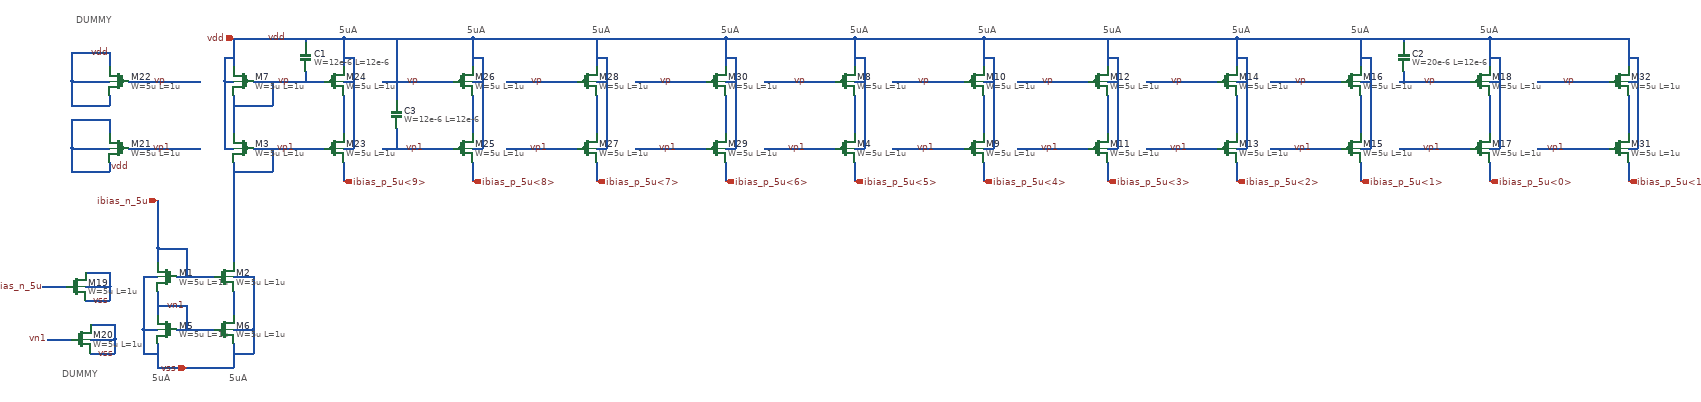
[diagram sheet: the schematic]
v {xschem version=3.4.8RC file_version=1.3}
G {}
K {}
V {}
S {}
F {}
E {}
T {5uA} -600 -260 0 0 0.2 0.2 {}
T {5uA} -440 -260 0 0 0.2 0.2 {}
T {5uA} 860 -990 0 0 0.2 0.2 {}
T {5uA} 1130 -990 0 0 0.2 0.2 {}
T {5uA} 1390 -990 0 0 0.2 0.2 {}
T {5uA} 1660 -990 0 0 0.2 0.2 {}
T {5uA} 1910 -990 0 0 0.2 0.2 {}
T {5uA} 2180 -990 0 0 0.2 0.2 {}
T {DUMMY} -760 -1010 0 0 0.4 0.4 {}
T {DUMMY} -790 -270 0 0 0.4 0.4 {}
T {5uA} -210 -990 0 0 0.2 0.2 {}
T {5uA} 60 -990 0 0 0.2 0.2 {}
T {5uA} 320 -990 0 0 0.2 0.2 {}
T {5uA} 590 -990 0 0 0.2 0.2 {}
N -550 -460 -470 -460 {lab=ibias_n_5u}
N -530 -520 -530 -460 {lab=ibias_n_5u}
N -590 -520 -530 -520 {lab=ibias_n_5u}
N -590 -520 -590 -490 {lab=ibias_n_5u}
N -590 -430 -590 -380 {lab=vn1}
N -590 -270 -430 -270 {lab=vss}
N -430 -430 -430 -380 {lab=#net1}
N -620 -460 -590 -460 {lab=vss}
N -620 -460 -620 -410 {lab=vss}
N -430 -460 -390 -460 {lab=vss}
N -390 -460 -390 -420 {lab=vss}
N -390 -420 -390 -410 {lab=vss}
N -390 -730 -240 -730 {lab=vp1}
N -430 -680 -350 -680 {lab=vp1}
N -350 -730 -350 -710 {lab=vp1}
N 870 -820 870 -760 {lab=#net2}
N -430 -960 -200 -960 {lab=vdd}
N -450 -730 -430 -730 {lab=vdd}
N 870 -730 890 -730 {lab=vdd}
N 870 -700 870 -660 {lab=ibias_p_5u<5>}
N -430 -700 -430 -590 {lab=vp1}
N -430 -530 -430 -490 {lab=vp1}
N -590 -540 -590 -520 {lab=ibias_n_5u}
N -550 -350 -470 -350 {lab=vn1}
N -590 -320 -590 -270 {lab=vss}
N -430 -320 -430 -270 {lab=vss}
N -620 -350 -590 -350 {lab=vss}
N -620 -350 -620 -300 {lab=vss}
N -620 -300 -590 -300 {lab=vss}
N -430 -350 -390 -350 {lab=vss}
N -390 -350 -390 -310 {lab=vss}
N -390 -310 -390 -300 {lab=vss}
N -430 -300 -390 -300 {lab=vss}
N -530 -400 -530 -350 {lab=vn1}
N -590 -400 -530 -400 {lab=vn1}
N -390 -410 -390 -350 {lab=vss}
N -620 -420 -620 -350 {lab=vss}
N -350 -710 -350 -680 {lab=vp1}
N -390 -870 -240 -870 {lab=vp}
N -430 -820 -350 -820 {lab=vp}
N -350 -870 -350 -850 {lab=vp}
N 870 -960 870 -900 {lab=vdd}
N -430 -960 -430 -900 {lab=vdd}
N -450 -870 -430 -870 {lab=vdd}
N -450 -920 -450 -870 {lab=vdd}
N -450 -920 -430 -920 {lab=vdd}
N 870 -870 890 -870 {lab=vdd}
N 890 -920 890 -870 {lab=vdd}
N 870 -920 890 -920 {lab=vdd}
N 870 -840 870 -800 {lab=#net2}
N -350 -850 -350 -820 {lab=vp}
N -430 -840 -430 -810 {lab=vp}
N -450 -870 -450 -730 {lab=vdd}
N 890 -880 890 -730 {lab=vdd}
N 950 -730 1100 -730 {lab=vp1}
N 1140 -820 1140 -760 {lab=#net3}
N 1140 -730 1160 -730 {lab=vdd}
N 1140 -700 1140 -660 {lab=ibias_p_5u<4>}
N 950 -870 1100 -870 {lab=vp}
N 1140 -960 1140 -900 {lab=vdd}
N 1140 -870 1160 -870 {lab=vdd}
N 1160 -920 1160 -870 {lab=vdd}
N 1140 -920 1160 -920 {lab=vdd}
N 1140 -840 1140 -800 {lab=#net3}
N 1160 -880 1160 -730 {lab=vdd}
N 870 -960 1140 -960 {lab=vdd}
N 1210 -730 1360 -730 {lab=vp1}
N 1400 -820 1400 -760 {lab=#net4}
N 1400 -730 1420 -730 {lab=vdd}
N 1400 -700 1400 -660 {lab=ibias_p_5u<3>}
N 1210 -870 1360 -870 {lab=vp}
N 1400 -870 1420 -870 {lab=vdd}
N 1420 -920 1420 -870 {lab=vdd}
N 1400 -920 1420 -920 {lab=vdd}
N 1400 -840 1400 -800 {lab=#net4}
N 1420 -880 1420 -730 {lab=vdd}
N 1480 -730 1630 -730 {lab=vp1}
N 1670 -820 1670 -760 {lab=#net5}
N 1670 -730 1690 -730 {lab=vdd}
N 1670 -700 1670 -660 {lab=ibias_p_5u<2>}
N 1480 -870 1630 -870 {lab=vp}
N 1670 -870 1690 -870 {lab=vdd}
N 1690 -920 1690 -870 {lab=vdd}
N 1670 -920 1690 -920 {lab=vdd}
N 1670 -840 1670 -800 {lab=#net5}
N 1690 -880 1690 -730 {lab=vdd}
N 1140 -960 1670 -960 {lab=vdd}
N 1670 -960 1670 -900 {lab=vdd}
N 1400 -960 1400 -900 {lab=vdd}
N 1740 -730 1890 -730 {lab=vp1}
N 1930 -820 1930 -760 {lab=#net6}
N 1930 -730 1950 -730 {lab=vdd}
N 1930 -700 1930 -660 {lab=ibias_p_5u<1>}
N 1740 -870 1890 -870 {lab=vp}
N 1930 -870 1950 -870 {lab=vdd}
N 1950 -920 1950 -870 {lab=vdd}
N 1930 -920 1950 -920 {lab=vdd}
N 1930 -840 1930 -800 {lab=#net6}
N 1950 -880 1950 -730 {lab=vdd}
N 2010 -730 2160 -730 {lab=vp1}
N 2200 -820 2200 -760 {lab=#net7}
N 2200 -730 2220 -730 {lab=vdd}
N 2200 -700 2200 -660 {lab=ibias_p_5u<0>}
N 2010 -870 2160 -870 {lab=vp}
N 2200 -870 2220 -870 {lab=vdd}
N 2220 -920 2220 -870 {lab=vdd}
N 2200 -920 2220 -920 {lab=vdd}
N 2200 -840 2200 -800 {lab=#net7}
N 2220 -880 2220 -730 {lab=vdd}
N 1670 -960 2200 -960 {lab=vdd}
N 2200 -960 2200 -900 {lab=vdd}
N 1930 -960 1930 -900 {lab=vdd}
N -590 -620 -590 -540 {lab=ibias_n_5u}
N -430 -590 -430 -530 {lab=vp1}
N -830 -440 -780 -440 {lab=ibias_n_5u}
N -740 -470 -690 -470 {lab=vss}
N -690 -470 -690 -440 {lab=vss}
N -740 -440 -690 -440 {lab=vss}
N -690 -440 -690 -410 {lab=vss}
N -740 -410 -690 -410 {lab=vss}
N -820 -330 -770 -330 {lab=vn1}
N -730 -360 -680 -360 {lab=vss}
N -680 -360 -680 -330 {lab=vss}
N -730 -330 -680 -330 {lab=vss}
N -680 -330 -680 -300 {lab=vss}
N -730 -300 -680 -300 {lab=vss}
N -650 -730 -500 -730 {lab=vp1}
N -650 -870 -500 -870 {lab=vp}
N -710 -870 -690 -870 {lab=vdd}
N -690 -930 -690 -900 {lab=vdd}
N -770 -930 -690 -930 {lab=vdd}
N -770 -930 -770 -870 {lab=vdd}
N -770 -870 -710 -870 {lab=vdd}
N -770 -870 -770 -820 {lab=vdd}
N -770 -820 -690 -820 {lab=vdd}
N -690 -840 -690 -820 {lab=vdd}
N -710 -730 -690 -730 {lab=vdd}
N -690 -790 -690 -760 {lab=vdd}
N -770 -790 -690 -790 {lab=vdd}
N -770 -790 -770 -730 {lab=vdd}
N -770 -730 -710 -730 {lab=vdd}
N -770 -730 -770 -680 {lab=vdd}
N -770 -680 -690 -680 {lab=vdd}
N -690 -700 -690 -680 {lab=vdd}
N -280 -960 -280 -950 {lab=vdd}
N -280 -890 -280 -870 {lab=vp}
N -200 -820 -200 -760 {lab=#net8}
N -200 -730 -180 -730 {lab=vdd}
N -200 -700 -200 -660 {lab=ibias_p_5u<9>}
N -200 -960 -200 -900 {lab=vdd}
N -200 -870 -180 -870 {lab=vdd}
N -180 -920 -180 -870 {lab=vdd}
N -200 -920 -180 -920 {lab=vdd}
N -200 -840 -200 -800 {lab=#net8}
N -180 -880 -180 -730 {lab=vdd}
N -120 -730 30 -730 {lab=vp1}
N 70 -820 70 -760 {lab=#net9}
N 70 -730 90 -730 {lab=vdd}
N 70 -700 70 -660 {lab=ibias_p_5u<8>}
N -120 -870 30 -870 {lab=vp}
N 70 -960 70 -900 {lab=vdd}
N 70 -870 90 -870 {lab=vdd}
N 90 -920 90 -870 {lab=vdd}
N 70 -920 90 -920 {lab=vdd}
N 70 -840 70 -800 {lab=#net9}
N 90 -880 90 -730 {lab=vdd}
N -200 -960 70 -960 {lab=vdd}
N 140 -730 290 -730 {lab=vp1}
N 330 -820 330 -760 {lab=#net10}
N 330 -730 350 -730 {lab=vdd}
N 330 -700 330 -660 {lab=ibias_p_5u<7>}
N 140 -870 290 -870 {lab=vp}
N 330 -870 350 -870 {lab=vdd}
N 350 -920 350 -870 {lab=vdd}
N 330 -920 350 -920 {lab=vdd}
N 330 -840 330 -800 {lab=#net10}
N 350 -880 350 -730 {lab=vdd}
N 410 -730 560 -730 {lab=vp1}
N 600 -820 600 -760 {lab=#net11}
N 600 -730 620 -730 {lab=vdd}
N 600 -700 600 -660 {lab=ibias_p_5u<6>}
N 410 -870 560 -870 {lab=vp}
N 600 -870 620 -870 {lab=vdd}
N 620 -920 620 -870 {lab=vdd}
N 600 -920 620 -920 {lab=vdd}
N 600 -840 600 -800 {lab=#net11}
N 620 -880 620 -730 {lab=vdd}
N 70 -960 600 -960 {lab=vdd}
N 600 -960 600 -900 {lab=vdd}
N 330 -960 330 -900 {lab=vdd}
N -90 -960 -90 -830 {lab=vdd}
N -90 -770 -90 -730 {lab=vp1}
N 600 -960 870 -960 {lab=vdd}
N 680 -870 830 -870 {lab=vp}
N 680 -730 830 -730 {lab=vp1}
N 2020 -960 2020 -950 {lab=vdd}
N 2020 -890 2020 -870 {lab=vp}
N 2300 -730 2450 -730 {lab=vp1}
N 2490 -820 2490 -760 {lab=#net12}
N 2490 -730 2510 -730 {lab=vdd}
N 2490 -700 2490 -660 {lab=ibias_p_5u<10>}
N 2300 -870 2450 -870 {lab=vp}
N 2490 -870 2510 -870 {lab=vdd}
N 2510 -920 2510 -870 {lab=vdd}
N 2490 -920 2510 -920 {lab=vdd}
N 2490 -840 2490 -800 {lab=#net12}
N 2510 -880 2510 -730 {lab=vdd}
N 2490 -960 2490 -900 {lab=vdd}
N 2200 -960 2490 -960 {lab=vdd}
N -430 -810 -430 -760 {lab=vp}
C {symbols/nfet_05v0.sym} -570 -460 0 1 {name=M1
L=1u
W=5u
nf=1
m=1
ad="'int((nf+1)/2) * W/nf * 0.18u'"
pd="'2*int((nf+1)/2) * (W/nf + 0.18u)'"
as="'int((nf+2)/2) * W/nf * 0.18u'"
ps="'2*int((nf+2)/2) * (W/nf + 0.18u)'"
nrd="'0.18u / W'" nrs="'0.18u / W'"
sa=0 sb=0 sd=0
model=nfet_05v0
spiceprefix=X
}
C {symbols/nfet_05v0.sym} -450 -460 0 0 {name=M2
L=1u
W=5u
nf=1
m=1
ad="'int((nf+1)/2) * W/nf * 0.18u'"
pd="'2*int((nf+1)/2) * (W/nf + 0.18u)'"
as="'int((nf+2)/2) * W/nf * 0.18u'"
ps="'2*int((nf+2)/2) * (W/nf + 0.18u)'"
nrd="'0.18u / W'" nrs="'0.18u / W'"
sa=0 sb=0 sd=0
model=nfet_05v0
spiceprefix=X
}
C {symbols/pfet_05v0.sym} -410 -730 0 1 {name=M3
L=1u
W=5u
nf=1
m=1
ad="'int((nf+1)/2) * W/nf * 0.18u'"
pd="'2*int((nf+1)/2) * (W/nf + 0.18u)'"
as="'int((nf+2)/2) * W/nf * 0.18u'"
ps="'2*int((nf+2)/2) * (W/nf + 0.18u)'"
nrd="'0.18u / W'" nrs="'0.18u / W'"
sa=0 sb=0 sd=0
model=pfet_05v0
spiceprefix=X
}
C {symbols/pfet_05v0.sym} 850 -730 0 0 {name=M4
L=1u
W=5u
nf=1
m=1
ad="'int((nf+1)/2) * W/nf * 0.18u'"
pd="'2*int((nf+1)/2) * (W/nf + 0.18u)'"
as="'int((nf+2)/2) * W/nf * 0.18u'"
ps="'2*int((nf+2)/2) * (W/nf + 0.18u)'"
nrd="'0.18u / W'" nrs="'0.18u / W'"
sa=0 sb=0 sd=0
model=pfet_05v0
spiceprefix=X
}
C {devices/lab_pin.sym} -320 -960 1 0 {name=l5 sig_type=std_logic lab=vdd}
C {symbols/nfet_05v0.sym} -570 -350 0 1 {name=M5
L=1u
W=5u
nf=1
m=1
ad="'int((nf+1)/2) * W/nf * 0.18u'"
pd="'2*int((nf+1)/2) * (W/nf + 0.18u)'"
as="'int((nf+2)/2) * W/nf * 0.18u'"
ps="'2*int((nf+2)/2) * (W/nf + 0.18u)'"
nrd="'0.18u / W'" nrs="'0.18u / W'"
sa=0 sb=0 sd=0
model=nfet_05v0
spiceprefix=X
}
C {symbols/nfet_05v0.sym} -450 -350 0 0 {name=M6
L=1u
W=5u
nf=1
m=1
ad="'int((nf+1)/2) * W/nf * 0.18u'"
pd="'2*int((nf+1)/2) * (W/nf + 0.18u)'"
as="'int((nf+2)/2) * W/nf * 0.18u'"
ps="'2*int((nf+2)/2) * (W/nf + 0.18u)'"
nrd="'0.18u / W'" nrs="'0.18u / W'"
sa=0 sb=0 sd=0
model=nfet_05v0
spiceprefix=X
}
C {symbols/pfet_05v0.sym} -410 -870 0 1 {name=M7
L=1u
W=5u
nf=1
m=1
ad="'int((nf+1)/2) * W/nf * 0.18u'"
pd="'2*int((nf+1)/2) * (W/nf + 0.18u)'"
as="'int((nf+2)/2) * W/nf * 0.18u'"
ps="'2*int((nf+2)/2) * (W/nf + 0.18u)'"
nrd="'0.18u / W'" nrs="'0.18u / W'"
sa=0 sb=0 sd=0
model=pfet_05v0
spiceprefix=X
}
C {symbols/pfet_05v0.sym} 850 -870 0 0 {name=M8
L=1u
W=5u
nf=1
m=1
ad="'int((nf+1)/2) * W/nf * 0.18u'"
pd="'2*int((nf+1)/2) * (W/nf + 0.18u)'"
as="'int((nf+2)/2) * W/nf * 0.18u'"
ps="'2*int((nf+2)/2) * (W/nf + 0.18u)'"
nrd="'0.18u / W'" nrs="'0.18u / W'"
sa=0 sb=0 sd=0
model=pfet_05v0
spiceprefix=X
}
C {devices/lab_pin.sym} -310 -870 1 0 {name=l7 sig_type=std_logic lab=vp}
C {devices/lab_pin.sym} -300 -730 1 0 {name=l3 sig_type=std_logic lab=vp1}
C {devices/lab_pin.sym} -530 -400 1 0 {name=l8 sig_type=std_logic lab=vn1}
C {symbols/pfet_05v0.sym} 1120 -730 0 0 {name=M9
L=1u
W=5u
nf=1
m=1
ad="'int((nf+1)/2) * W/nf * 0.18u'"
pd="'2*int((nf+1)/2) * (W/nf + 0.18u)'"
as="'int((nf+2)/2) * W/nf * 0.18u'"
ps="'2*int((nf+2)/2) * (W/nf + 0.18u)'"
nrd="'0.18u / W'" nrs="'0.18u / W'"
sa=0 sb=0 sd=0
model=pfet_05v0
spiceprefix=X
}
C {symbols/pfet_05v0.sym} 1120 -870 0 0 {name=M10
L=1u
W=5u
nf=1
m=1
ad="'int((nf+1)/2) * W/nf * 0.18u'"
pd="'2*int((nf+1)/2) * (W/nf + 0.18u)'"
as="'int((nf+2)/2) * W/nf * 0.18u'"
ps="'2*int((nf+2)/2) * (W/nf + 0.18u)'"
nrd="'0.18u / W'" nrs="'0.18u / W'"
sa=0 sb=0 sd=0
model=pfet_05v0
spiceprefix=X
}
C {devices/lab_pin.sym} 1030 -870 1 0 {name=l10 sig_type=std_logic lab=vp}
C {devices/lab_pin.sym} 1040 -730 1 0 {name=l11 sig_type=std_logic lab=vp1}
C {symbols/pfet_05v0.sym} 1380 -730 0 0 {name=M11
L=1u
W=5u
nf=1
m=1
ad="'int((nf+1)/2) * W/nf * 0.18u'"
pd="'2*int((nf+1)/2) * (W/nf + 0.18u)'"
as="'int((nf+2)/2) * W/nf * 0.18u'"
ps="'2*int((nf+2)/2) * (W/nf + 0.18u)'"
nrd="'0.18u / W'" nrs="'0.18u / W'"
sa=0 sb=0 sd=0
model=pfet_05v0
spiceprefix=X
}
C {symbols/pfet_05v0.sym} 1380 -870 0 0 {name=M12
L=1u
W=5u
nf=1
m=1
ad="'int((nf+1)/2) * W/nf * 0.18u'"
pd="'2*int((nf+1)/2) * (W/nf + 0.18u)'"
as="'int((nf+2)/2) * W/nf * 0.18u'"
ps="'2*int((nf+2)/2) * (W/nf + 0.18u)'"
nrd="'0.18u / W'" nrs="'0.18u / W'"
sa=0 sb=0 sd=0
model=pfet_05v0
spiceprefix=X
}
C {devices/lab_pin.sym} 1290 -870 1 0 {name=l13 sig_type=std_logic lab=vp}
C {devices/lab_pin.sym} 1300 -730 1 0 {name=l14 sig_type=std_logic lab=vp1}
C {symbols/pfet_05v0.sym} 1650 -730 0 0 {name=M13
L=1u
W=5u
nf=1
m=1
ad="'int((nf+1)/2) * W/nf * 0.18u'"
pd="'2*int((nf+1)/2) * (W/nf + 0.18u)'"
as="'int((nf+2)/2) * W/nf * 0.18u'"
ps="'2*int((nf+2)/2) * (W/nf + 0.18u)'"
nrd="'0.18u / W'" nrs="'0.18u / W'"
sa=0 sb=0 sd=0
model=pfet_05v0
spiceprefix=X
}
C {symbols/pfet_05v0.sym} 1650 -870 0 0 {name=M14
L=1u
W=5u
nf=1
m=1
ad="'int((nf+1)/2) * W/nf * 0.18u'"
pd="'2*int((nf+1)/2) * (W/nf + 0.18u)'"
as="'int((nf+2)/2) * W/nf * 0.18u'"
ps="'2*int((nf+2)/2) * (W/nf + 0.18u)'"
nrd="'0.18u / W'" nrs="'0.18u / W'"
sa=0 sb=0 sd=0
model=pfet_05v0
spiceprefix=X
}
C {devices/lab_pin.sym} 1560 -870 1 0 {name=l16 sig_type=std_logic lab=vp}
C {devices/lab_pin.sym} 1570 -730 1 0 {name=l17 sig_type=std_logic lab=vp1}
C {symbols/pfet_05v0.sym} 1910 -730 0 0 {name=M15
L=1u
W=5u
nf=1
m=1
ad="'int((nf+1)/2) * W/nf * 0.18u'"
pd="'2*int((nf+1)/2) * (W/nf + 0.18u)'"
as="'int((nf+2)/2) * W/nf * 0.18u'"
ps="'2*int((nf+2)/2) * (W/nf + 0.18u)'"
nrd="'0.18u / W'" nrs="'0.18u / W'"
sa=0 sb=0 sd=0
model=pfet_05v0
spiceprefix=X
}
C {symbols/pfet_05v0.sym} 1910 -870 0 0 {name=M16
L=1u
W=5u
nf=1
m=1
ad="'int((nf+1)/2) * W/nf * 0.18u'"
pd="'2*int((nf+1)/2) * (W/nf + 0.18u)'"
as="'int((nf+2)/2) * W/nf * 0.18u'"
ps="'2*int((nf+2)/2) * (W/nf + 0.18u)'"
nrd="'0.18u / W'" nrs="'0.18u / W'"
sa=0 sb=0 sd=0
model=pfet_05v0
spiceprefix=X
}
C {devices/lab_pin.sym} 1820 -870 1 0 {name=l19 sig_type=std_logic lab=vp}
C {devices/lab_pin.sym} 1830 -730 1 0 {name=l20 sig_type=std_logic lab=vp1}
C {symbols/pfet_05v0.sym} 2180 -730 0 0 {name=M17
L=1u
W=5u
nf=1
m=1
ad="'int((nf+1)/2) * W/nf * 0.18u'"
pd="'2*int((nf+1)/2) * (W/nf + 0.18u)'"
as="'int((nf+2)/2) * W/nf * 0.18u'"
ps="'2*int((nf+2)/2) * (W/nf + 0.18u)'"
nrd="'0.18u / W'" nrs="'0.18u / W'"
sa=0 sb=0 sd=0
model=pfet_05v0
spiceprefix=X
}
C {symbols/pfet_05v0.sym} 2180 -870 0 0 {name=M18
L=1u
W=5u
nf=1
m=1
ad="'int((nf+1)/2) * W/nf * 0.18u'"
pd="'2*int((nf+1)/2) * (W/nf + 0.18u)'"
as="'int((nf+2)/2) * W/nf * 0.18u'"
ps="'2*int((nf+2)/2) * (W/nf + 0.18u)'"
nrd="'0.18u / W'" nrs="'0.18u / W'"
sa=0 sb=0 sd=0
model=pfet_05v0
spiceprefix=X
}
C {devices/lab_pin.sym} 2090 -870 1 0 {name=l22 sig_type=std_logic lab=vp}
C {devices/lab_pin.sym} 2100 -730 1 0 {name=l23 sig_type=std_logic lab=vp1}
C {ipin.sym} -590 -620 0 0 {name=p1 lab=ibias_n_5u}
C {iopin.sym} -430 -960 0 0 {name=p2 lab=vdd}
C {iopin.sym} -530 -270 0 0 {name=p3 lab=vss}
C {devices/title.sym} 20 -210 0 0 {name=l1 author="GlobalFoundries PDK VSP"}
C {opin.sym} 870 -660 1 0 {name=p11 lab=ibias_p_5u<5>}
C {opin.sym} 1140 -660 1 0 {name=p4 lab=ibias_p_5u<4>}
C {opin.sym} 1400 -660 1 0 {name=p5 lab=ibias_p_5u<3>}
C {opin.sym} 1670 -660 1 0 {name=p6 lab=ibias_p_5u<2>}
C {opin.sym} 1930 -660 1 0 {name=p7 lab=ibias_p_5u<1>}
C {opin.sym} 2200 -660 1 0 {name=p8 lab=ibias_p_5u<0>}
C {symbols/nfet_05v0.sym} -760 -440 0 0 {name=M19
L=1u
W=5u
nf=1
m=2
ad="'int((nf+1)/2) * W/nf * 0.18u'"
pd="'2*int((nf+1)/2) * (W/nf + 0.18u)'"
as="'int((nf+2)/2) * W/nf * 0.18u'"
ps="'2*int((nf+2)/2) * (W/nf + 0.18u)'"
nrd="'0.18u / W'" nrs="'0.18u / W'"
sa=0 sb=0 sd=0
model=nfet_05v0
spiceprefix=X
}
C {devices/lab_pin.sym} -830 -440 1 0 {name=l2 sig_type=std_logic lab=ibias_n_5u}
C {devices/lab_pin.sym} -690 -410 3 0 {name=l4 sig_type=std_logic lab=vss}
C {symbols/nfet_05v0.sym} -750 -330 0 0 {name=M20
L=1u
W=5u
nf=1
m=2
ad="'int((nf+1)/2) * W/nf * 0.18u'"
pd="'2*int((nf+1)/2) * (W/nf + 0.18u)'"
as="'int((nf+2)/2) * W/nf * 0.18u'"
ps="'2*int((nf+2)/2) * (W/nf + 0.18u)'"
nrd="'0.18u / W'" nrs="'0.18u / W'"
sa=0 sb=0 sd=0
model=nfet_05v0
spiceprefix=X
}
C {devices/lab_pin.sym} -820 -330 1 0 {name=l6 sig_type=std_logic lab=vn1}
C {devices/lab_pin.sym} -680 -300 3 0 {name=l9 sig_type=std_logic lab=vss}
C {symbols/pfet_05v0.sym} -670 -730 0 1 {name=M21
L=1u
W=5u
nf=1
m=2
ad="'int((nf+1)/2) * W/nf * 0.18u'"
pd="'2*int((nf+1)/2) * (W/nf + 0.18u)'"
as="'int((nf+2)/2) * W/nf * 0.18u'"
ps="'2*int((nf+2)/2) * (W/nf + 0.18u)'"
nrd="'0.18u / W'" nrs="'0.18u / W'"
sa=0 sb=0 sd=0
model=pfet_05v0
spiceprefix=X
}
C {symbols/pfet_05v0.sym} -670 -870 0 1 {name=M22
L=1u
W=5u
nf=1
m=2
ad="'int((nf+1)/2) * W/nf * 0.18u'"
pd="'2*int((nf+1)/2) * (W/nf + 0.18u)'"
as="'int((nf+2)/2) * W/nf * 0.18u'"
ps="'2*int((nf+2)/2) * (W/nf + 0.18u)'"
nrd="'0.18u / W'" nrs="'0.18u / W'"
sa=0 sb=0 sd=0
model=pfet_05v0
spiceprefix=X
}
C {devices/lab_pin.sym} -570 -870 1 0 {name=l12 sig_type=std_logic lab=vp}
C {devices/lab_pin.sym} -560 -730 1 0 {name=l15 sig_type=std_logic lab=vp1}
C {devices/lab_pin.sym} -690 -930 1 0 {name=l18 sig_type=std_logic lab=vdd}
C {devices/lab_pin.sym} -690 -690 2 0 {name=l21 sig_type=std_logic lab=vdd}
C {symbols/cap_mim_2f0fF.sym} -280 -920 0 0 {name=C1
W=12e-6
L=12e-6
model=cap_mim_2f0fF
spiceprefix=X
m=1}
C {symbols/pfet_05v0.sym} -220 -730 0 0 {name=M23
L=1u
W=5u
nf=1
m=1
ad="'int((nf+1)/2) * W/nf * 0.18u'"
pd="'2*int((nf+1)/2) * (W/nf + 0.18u)'"
as="'int((nf+2)/2) * W/nf * 0.18u'"
ps="'2*int((nf+2)/2) * (W/nf + 0.18u)'"
nrd="'0.18u / W'" nrs="'0.18u / W'"
sa=0 sb=0 sd=0
model=pfet_05v0
spiceprefix=X
}
C {symbols/pfet_05v0.sym} -220 -870 0 0 {name=M24
L=1u
W=5u
nf=1
m=1
ad="'int((nf+1)/2) * W/nf * 0.18u'"
pd="'2*int((nf+1)/2) * (W/nf + 0.18u)'"
as="'int((nf+2)/2) * W/nf * 0.18u'"
ps="'2*int((nf+2)/2) * (W/nf + 0.18u)'"
nrd="'0.18u / W'" nrs="'0.18u / W'"
sa=0 sb=0 sd=0
model=pfet_05v0
spiceprefix=X
}
C {symbols/pfet_05v0.sym} 50 -730 0 0 {name=M25
L=1u
W=5u
nf=1
m=1
ad="'int((nf+1)/2) * W/nf * 0.18u'"
pd="'2*int((nf+1)/2) * (W/nf + 0.18u)'"
as="'int((nf+2)/2) * W/nf * 0.18u'"
ps="'2*int((nf+2)/2) * (W/nf + 0.18u)'"
nrd="'0.18u / W'" nrs="'0.18u / W'"
sa=0 sb=0 sd=0
model=pfet_05v0
spiceprefix=X
}
C {symbols/pfet_05v0.sym} 50 -870 0 0 {name=M26
L=1u
W=5u
nf=1
m=1
ad="'int((nf+1)/2) * W/nf * 0.18u'"
pd="'2*int((nf+1)/2) * (W/nf + 0.18u)'"
as="'int((nf+2)/2) * W/nf * 0.18u'"
ps="'2*int((nf+2)/2) * (W/nf + 0.18u)'"
nrd="'0.18u / W'" nrs="'0.18u / W'"
sa=0 sb=0 sd=0
model=pfet_05v0
spiceprefix=X
}
C {devices/lab_pin.sym} -40 -870 1 0 {name=l24 sig_type=std_logic lab=vp}
C {devices/lab_pin.sym} -30 -730 1 0 {name=l25 sig_type=std_logic lab=vp1}
C {symbols/pfet_05v0.sym} 310 -730 0 0 {name=M27
L=1u
W=5u
nf=1
m=1
ad="'int((nf+1)/2) * W/nf * 0.18u'"
pd="'2*int((nf+1)/2) * (W/nf + 0.18u)'"
as="'int((nf+2)/2) * W/nf * 0.18u'"
ps="'2*int((nf+2)/2) * (W/nf + 0.18u)'"
nrd="'0.18u / W'" nrs="'0.18u / W'"
sa=0 sb=0 sd=0
model=pfet_05v0
spiceprefix=X
}
C {symbols/pfet_05v0.sym} 310 -870 0 0 {name=M28
L=1u
W=5u
nf=1
m=1
ad="'int((nf+1)/2) * W/nf * 0.18u'"
pd="'2*int((nf+1)/2) * (W/nf + 0.18u)'"
as="'int((nf+2)/2) * W/nf * 0.18u'"
ps="'2*int((nf+2)/2) * (W/nf + 0.18u)'"
nrd="'0.18u / W'" nrs="'0.18u / W'"
sa=0 sb=0 sd=0
model=pfet_05v0
spiceprefix=X
}
C {devices/lab_pin.sym} 220 -870 1 0 {name=l26 sig_type=std_logic lab=vp}
C {devices/lab_pin.sym} 230 -730 1 0 {name=l27 sig_type=std_logic lab=vp1}
C {symbols/pfet_05v0.sym} 580 -730 0 0 {name=M29
L=1u
W=5u
nf=1
m=1
ad="'int((nf+1)/2) * W/nf * 0.18u'"
pd="'2*int((nf+1)/2) * (W/nf + 0.18u)'"
as="'int((nf+2)/2) * W/nf * 0.18u'"
ps="'2*int((nf+2)/2) * (W/nf + 0.18u)'"
nrd="'0.18u / W'" nrs="'0.18u / W'"
sa=0 sb=0 sd=0
model=pfet_05v0
spiceprefix=X
}
C {symbols/pfet_05v0.sym} 580 -870 0 0 {name=M30
L=1u
W=5u
nf=1
m=1
ad="'int((nf+1)/2) * W/nf * 0.18u'"
pd="'2*int((nf+1)/2) * (W/nf + 0.18u)'"
as="'int((nf+2)/2) * W/nf * 0.18u'"
ps="'2*int((nf+2)/2) * (W/nf + 0.18u)'"
nrd="'0.18u / W'" nrs="'0.18u / W'"
sa=0 sb=0 sd=0
model=pfet_05v0
spiceprefix=X
}
C {devices/lab_pin.sym} 490 -870 1 0 {name=l28 sig_type=std_logic lab=vp}
C {devices/lab_pin.sym} 500 -730 1 0 {name=l29 sig_type=std_logic lab=vp1}
C {opin.sym} -200 -660 1 0 {name=p9 lab=ibias_p_5u<9>}
C {opin.sym} 70 -660 1 0 {name=p10 lab=ibias_p_5u<8>}
C {opin.sym} 330 -660 1 0 {name=p12 lab=ibias_p_5u<7>}
C {opin.sym} 600 -660 1 0 {name=p13 lab=ibias_p_5u<6>}
C {symbols/cap_mim_2f0fF.sym} -90 -800 0 0 {name=C3
W=12e-6
L=12e-6
model=cap_mim_2f0fF
spiceprefix=X
m=1}
C {devices/lab_pin.sym} 770 -870 1 0 {name=l30 sig_type=std_logic lab=vp}
C {devices/lab_pin.sym} 770 -730 1 0 {name=l31 sig_type=std_logic lab=vp1}
C {symbols/cap_mim_2f0fF.sym} 2020 -920 0 0 {name=C2
W=20e-6
L=12e-6
model=cap_mim_2f0fF
spiceprefix=X
m=1}
C {symbols/pfet_05v0.sym} 2470 -730 0 0 {name=M31
L=1u
W=5u
nf=1
m=1
ad="'int((nf+1)/2) * W/nf * 0.18u'"
pd="'2*int((nf+1)/2) * (W/nf + 0.18u)'"
as="'int((nf+2)/2) * W/nf * 0.18u'"
ps="'2*int((nf+2)/2) * (W/nf + 0.18u)'"
nrd="'0.18u / W'" nrs="'0.18u / W'"
sa=0 sb=0 sd=0
model=pfet_05v0
spiceprefix=X
}
C {symbols/pfet_05v0.sym} 2470 -870 0 0 {name=M32
L=1u
W=5u
nf=1
m=1
ad="'int((nf+1)/2) * W/nf * 0.18u'"
pd="'2*int((nf+1)/2) * (W/nf + 0.18u)'"
as="'int((nf+2)/2) * W/nf * 0.18u'"
ps="'2*int((nf+2)/2) * (W/nf + 0.18u)'"
nrd="'0.18u / W'" nrs="'0.18u / W'"
sa=0 sb=0 sd=0
model=pfet_05v0
spiceprefix=X
}
C {devices/lab_pin.sym} 2380 -870 1 0 {name=l32 sig_type=std_logic lab=vp}
C {devices/lab_pin.sym} 2360 -730 1 0 {name=l33 sig_type=std_logic lab=vp1}
C {opin.sym} 2490 -660 1 0 {name=p14 lab=ibias_p_5u<10>}
